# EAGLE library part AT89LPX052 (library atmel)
LP2052 - 4052 MICROCONTROLLER 2 -4 Kbytes FLASH 2.4-5.5 V full static

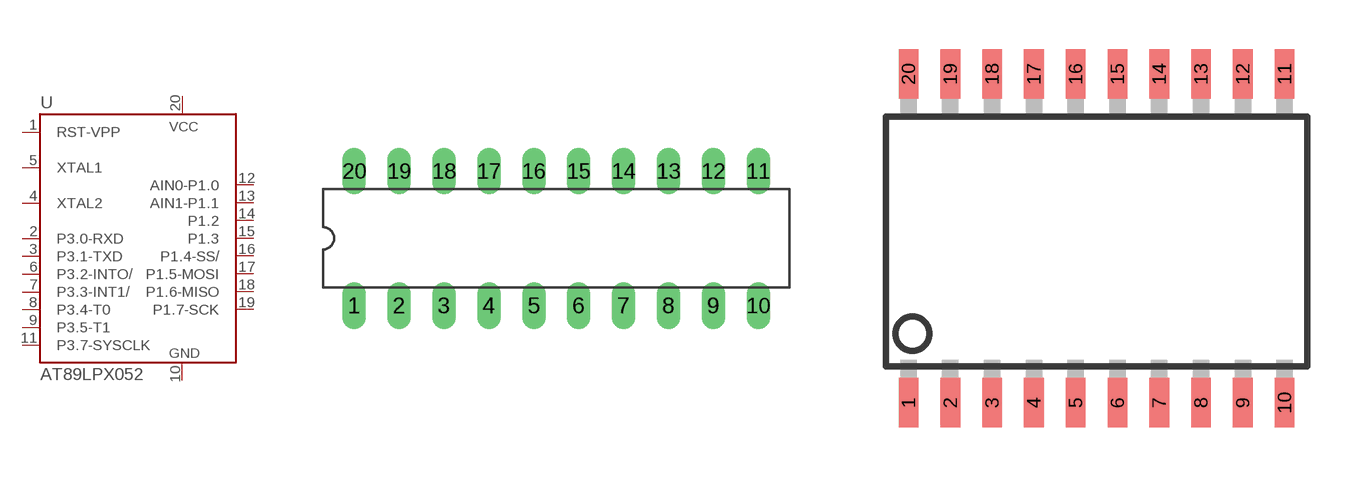
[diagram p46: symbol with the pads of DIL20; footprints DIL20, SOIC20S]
Designator prefix -

## AT89LPX052-DIL  [DIL20]
1  RST-VPP  in
2  P3.0-RXD
3  P3.1-TXD
4  XTAL2  out
5  XTAL1  in
6  P3.2-INTO/
7  P3.3-INT1/
8  P3.4-T0
9  P3.5-T1
10  GND  pwr
11  P3.7-SYSCLK
12  AIN0-P1.0
13  AIN1-P1.1
14  P1.2
15  P1.3
16  P1.4-SS/
17  P1.5-MOSI
18  P1.6-MISO
19  P1.7-SCK
20  VCC  pwr

## AT89LPX052-SOIC  [SOIC20S]
Pads as for DIL20

## AT89LPX052SSOP  [SSOP20D8]
Pads as for DIL20

## Footprint DIL20 (pad centres in mm)
Dual In Line
drill 0.813 long: 1 -11.43,-3.81; 2 -8.89,-3.81; 3 -6.35,-3.81; 4 -3.81,-3.81; 5 -1.27,-3.81; 6 1.27,-3.81; 7 3.81,-3.81; 8 6.35,-3.81; 9 8.89,-3.81; 10 11.43,-3.81; 11 11.43,3.81; 12 8.89,3.81; 13 6.35,3.81; 14 3.81,3.81; 15 1.27,3.81; 16 -1.27,3.81; 17 -3.81,3.81; 18 -6.35,3.81; 19 -8.89,3.81; 20 -11.43,3.81

## Footprint SOIC20S (pad centres in mm)
Wide Plastic Gull Wing Small Outline Package
smd 0.6 x 1.5: 1 -5.715,-5; 2 -4.445,-5; 3 -3.175,-5; 4 -1.905,-5; 5 -0.635,-5; 6 0.635,-5; 7 1.905,-5; 8 3.175,-5; 9 4.445,-5; 10 5.715,-5; 11 5.715,5; 12 4.445,5; 13 3.175,5; 14 1.905,5; 15 0.635,5; 16 -0.635,5; 17 -1.905,5; 18 -3.175,5; 19 -4.445,5; 20 -5.715,5

## Footprint SSOP20D8 (pad centres in mm)
Plastic Shrink Small Outline Package
smd 0.305 x 1.245: 1 -2.794,-3.353; 2 -2.159,-3.353; 3 -1.524,-3.353; 4 -0.889,-3.353; 5 -0.254,-3.353; 6 0.381,-3.353; 7 1.016,-3.353; 8 1.651,-3.353; 9 2.286,-3.353; 10 2.921,-3.353; 11 2.921,3.251; 12 2.286,3.251; 13 1.651,3.251; 14 1.016,3.251; 15 0.381,3.251; 16 -0.254,3.251; 17 -0.889,3.251; 18 -1.524,3.251; 19 -2.159,3.251; 20 -2.794,3.251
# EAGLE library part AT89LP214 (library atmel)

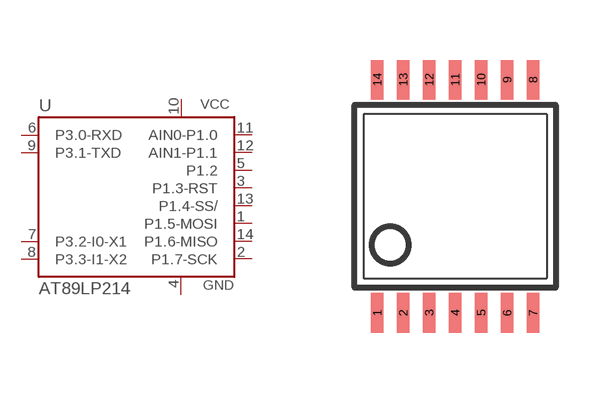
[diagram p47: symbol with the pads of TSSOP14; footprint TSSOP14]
Designator prefix -

## AT89LP214  [TSSOP14]
1  P1.5-MOSI
2  P1.7-SCK
3  P1.3-RST
4  GND  pwr
5  P1.2
6  P3.0-RXD
7  P3.2-I0-X1
8  P3.3-I1-X2
9  P3.1-TXD
10  VCC  pwr
11  AIN0-P1.0
12  AIN1-P1.1
13  P1.4-SS/
14  P1.6-MISO

## Footprint TSSOP14 (pad centres in mm)
smd 0.305 x 0.991: 1 -1.95,-2.918; 2 -1.3,-2.918; 3 -0.65,-2.918; 4 0,-2.918; 5 0.65,-2.918; 6 1.3,-2.918; 7 1.95,-2.918; 8 1.95,2.918; 9 1.3,2.918; 10 0.65,2.918; 11 0,2.918; 12 -0.65,2.918; 13 -1.3,2.918; 14 -1.95,2.918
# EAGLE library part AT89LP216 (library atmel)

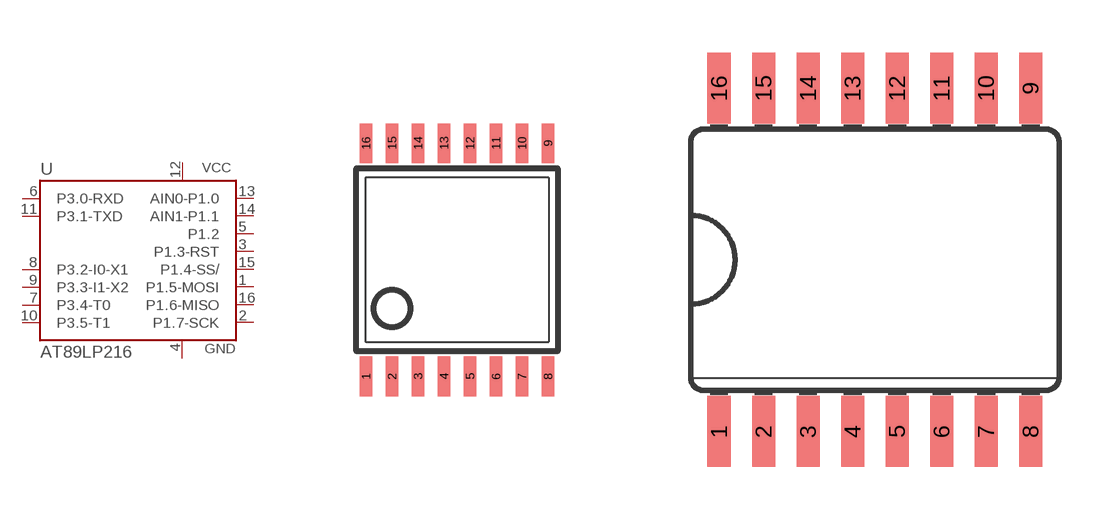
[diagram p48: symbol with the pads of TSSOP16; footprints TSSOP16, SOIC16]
Designator prefix -

## AT89LP216  [TSSOP16]
1  P1.5-MOSI
2  P1.7-SCK
3  P1.3-RST
4  GND  pwr
5  P1.2
6  P3.0-RXD
7  P3.4-T0
8  P3.2-I0-X1
9  P3.3-I1-X2
10  P3.5-T1
11  P3.1-TXD
12  VCC  pwr
13  AIN0-P1.0
14  AIN1-P1.1
15  P1.4-SS/
16  P1.6-MISO

## AT89LP216SOIC  [SOIC16]
Pads as for TSSOP16

## Footprint TSSOP16 (pad centres in mm)
smd 0.305 x 0.991: 1 -2.275,-2.918; 2 -1.625,-2.918; 3 -0.975,-2.918; 4 -0.325,-2.918; 5 0.325,-2.918; 6 0.975,-2.918; 7 1.625,-2.918; 8 2.275,-2.918; 9 2.275,2.918; 10 1.625,2.918; 11 0.975,2.918; 12 0.325,2.918; 13 -0.325,2.918; 14 -0.975,2.918; 15 -1.625,2.918; 16 -2.275,2.918

## Footprint SOIC16 (pad centres in mm)
smd 0.66 x 2.032: 1 -4.445,-4.902; 2 -3.175,-4.902; 3 -1.905,-4.902; 4 -0.635,-4.902; 5 0.635,-4.902; 6 1.905,-4.902; 7 3.175,-4.902; 8 4.445,-4.902; 9 4.445,4.902; 10 3.175,4.902; 11 1.905,4.902; 12 0.635,4.902; 13 -0.635,4.902; 14 -1.905,4.902; 15 -3.175,4.902; 16 -4.445,4.902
